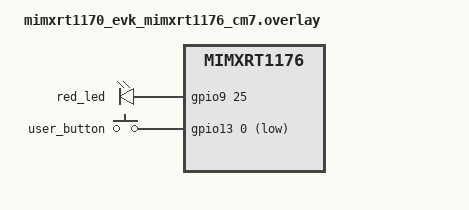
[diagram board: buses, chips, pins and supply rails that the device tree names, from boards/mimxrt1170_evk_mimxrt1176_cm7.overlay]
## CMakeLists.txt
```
# Copyright 2024-2026 NXP
# SPDX-License-Identifier: Apache-2.0

cmake_minimum_required(VERSION 3.20.0)

find_package(Zephyr REQUIRED HINTS $ENV{ZEPHYR_BASE})
project(android_link)

target_sources(app PRIVATE
  src/main.c
  src/touch.c
  src/display.c
  src/control_msg.c
)
target_sources_ifdef(CONFIG_ANDROID_LINK_MIC app PRIVATE src/mic_mode.c)

target_include_directories(app PRIVATE src)

if(CONFIG_NET_STACK_CODE_RELOCATE)
  # Relocate the networking stack and the L2 layer into the RAM named by
  # CONFIG_NET_STACK_CODE_RAM_NAME (ITCM on the RT1170), as the original demo does.
  zephyr_code_relocate(LIBRARY subsys__net__ip
    LOCATION "${CONFIG_NET_STACK_CODE_RAM_NAME}_TEXT" NOKEEP)
  zephyr_code_relocate(LIBRARY subsys__net
    LOCATION "${CONFIG_NET_STACK_CODE_RAM_NAME}_TEXT" NOKEEP)
  if(CONFIG_NET_L2_ETHERNET)
    zephyr_code_relocate(LIBRARY drivers__ethernet
      LOCATION "${CONFIG_NET_STACK_CODE_RAM_NAME}_TEXT" NOKEEP)
    zephyr_code_relocate(LIBRARY subsys__net__l2__ethernet
      LOCATION "${CONFIG_NET_STACK_CODE_RAM_NAME}_TEXT" NOKEEP)
  endif()
endif()
```

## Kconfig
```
# Copyright 2024-2026 NXP
# SPDX-License-Identifier: Apache-2.0

DT_CHOSEN_Z_DISPLAY := zephyr,display
DT_DISPLAY_PATH := $(dt_chosen_path,$(DT_CHOSEN_Z_DISPLAY))
DT_DISPLAY_WIDTH := $(dt_node_int_prop_int,$(DT_DISPLAY_PATH),width)
DT_DISPLAY_HEIGHT := $(dt_node_int_prop_int,$(DT_DISPLAY_PATH),height)
# A frame of the panel's size in RGB565
DT_DISPLAY_FRAME_SIZE := $(mul,$(mul,$(DT_DISPLAY_WIDTH),$(DT_DISPLAY_HEIGHT)),2)

# The decoder's pool holds frames of the panel's size
config MPIPE_IMG_JPEG_DECODER_MAX_OUT_FRAME_SIZE
	default $(DT_DISPLAY_FRAME_SIZE) if $(dt_chosen_enabled,$(DT_CHOSEN_Z_DISPLAY))

source "Kconfig.zephyr"

config ANDROID_LINK_FRAME_WIDTH
	int "Width of the frames the phone sends"
	default $(DT_DISPLAY_WIDTH)
	help
	  Width in pixels of the JPEG frames the phone streams, which the caps
	  filter pins behind the parser. It defaults to the width of the chosen
	  display and the phone's server must be launched with the same value
	  (WIDTH in its launch script).

config ANDROID_LINK_FRAME_HEIGHT
	int "Height of the frames the phone sends"
	default $(DT_DISPLAY_HEIGHT)
	help
	  Height in pixels of the JPEG frames the phone streams. It defaults to
	  the height of the chosen display and the phone's server must be
	  launched with the same value (HEIGHT in its launch script).

config NET_STACK_CODE_RELOCATE
	bool "Relocate networking code into RAM"
	select CODE_DATA_RELOCATION
	help
	  Relocate networking code into RAM. Can improve performance on
	  platforms with fast code RAM.

if NET_STACK_CODE_RELOCATE

config NET_STACK_CODE_RAM_NAME
	string "Networking code RAM location"
	default "RAM"
	help
	  Region to relocate networking code to

endif # NET_STACK_CODE_RELOCATE

config ANDROID_LINK_AUDIO
	bool "Play the phone's audio"
	default y
	depends on MPIPE_AUD
	help
	  Accept the phone's audio connection and play the raw PCM it carries
	  through a second pipeline ending in the I2S codec sink. The phone
	  must be launched with audio enabled and the raw codec.

config ANDROID_LINK_MIC
	bool "Send the board's microphone to the phone"
	default y
	depends on MPIPE_AUD && AUDIO_DMIC
	help
	  Accept a fourth connection from the phone, after the control one,
	  and send it the board's microphone as raw PCM, 16 kHz, 32-bit, two
	  channels, through a third pipeline from the DMIC source to a socket
	  sink. What the phone does with the stream, play it on its speaker,
	  feed it to the applications recording from its microphone, or drop
	  it, is set by a control message. The phone must be launched with the
	  microphone channel enabled.

config ANDROID_LINK_MIC_GAIN
	int "Gain applied to the board's microphone, in percent"
	depends on ANDROID_LINK_MIC
	range 0 1000
	default 200
	help
	  Gain of the aud_gain element in the microphone pipeline, 100 for
	  unity. A digital microphone's speech peaks well below full scale;
	  200 (+6 dB) brings it to the level of a phone's microphone. 0 mutes.

config ANDROID_LINK_PORT
	int "TCP port the board listens on"
	range 1 65535
	default 5000
	help
	  Port of the listening socket the phone's server connects to for the
	  video, audio, control and microphone streams (REMOTE_PORT in its
	  launch script).

if WIFI

config ANDROID_LINK_WIFI_SSID
	string "Name of the board's Wi-Fi network"
	default "zephyr-link"
	help
	  SSID of the soft-AP the board starts. The phone's server joins it
	  by itself when launched with the same name (WIFI_SSID).

config ANDROID_LINK_WIFI_PSK
	string "Passphrase of the board's Wi-Fi network"
	default "zephyrdemo"
	help
	  WPA2 passphrase of the soft-AP, at least 8 characters; empty for an
	  open network. The phone's server needs the same value (WIFI_PSK).

endif # WIFI

choice
	prompt "Control Event protocol"
	default CONTROL_EVENT_TCP

config CONTROL_EVENT_UDP
	bool "Control UDP protocol"
	help
	  Control events are reported using the UDP protocol.

config CONTROL_EVENT_TCP
	bool "Control TCP protocol"
	help
	  Touch events are reported using the TCP protocol.

endchoice
```

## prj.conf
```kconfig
#
# Copyright 2024-2026 NXP
#
# SPDX-License-Identifier: Apache-2.0
#

# Kernel options
CONFIG_MAIN_STACK_SIZE=8192
CONFIG_INIT_STACKS=y

# Shell
CONFIG_SHELL=y
CONFIG_NET_SHELL=y
CONFIG_DEVICE_SHELL=y

# Logging
CONFIG_PRINTK=y
CONFIG_LOG=y
CONFIG_NET_LOG=y

# Display
CONFIG_DISPLAY=y

# mpipe media pipeline framework
CONFIG_MPIPE=y
# Audio capabilities carry five fields; an intersection may hold one more
CONFIG_MPIPE_STRUCTURE_MAX_FIELDS=6
CONFIG_MPIPE_BASE=y
CONFIG_MPIPE_BASE_CAPS_FILTER=y
CONFIG_MPIPE_BASE_QUEUE=y
# Video: the source and two queues; audio and microphone: a source and a queue
# each; plus slack
CONFIG_MPIPE_THREADS_NUM=10
CONFIG_MPIPE_THREAD_STACK_SIZE=4096
CONFIG_MPIPE_NET=y
CONFIG_MPIPE_IMG=y
CONFIG_MPIPE_IMG_JPEG_DECODER=y
CONFIG_MPIPE_DISP=y
# The overlay draws the demo's messages on the frames; its text comes from the
# character framebuffer's built-in bitmap fonts
CONFIG_MPIPE_VID=y
CONFIG_MPIPE_VID_OVERLAY=y
CONFIG_CHARACTER_FRAMEBUFFER=y
CONFIG_CHARACTER_FRAMEBUFFER_USE_DEFAULT_FONTS=y
CONFIG_MPIPE_AUD=y
CONFIG_MPIPE_PLAYER=y
# One player per pipeline: video, audio and microphone
CONFIG_MPIPE_PLAYER_NUM=3
CONFIG_ZBUS_PRIORITY_BOOST=n

# Audio output: the I2S codec sink, fed 10 ms blocks of 48 kHz 16-bit stereo
# (1920 bytes) from a slab of up to 32 of them: 15 queued, up to 16 in the I2S
# driver's queue, the one being filled.
CONFIG_I2S=y
CONFIG_AUDIO_CODEC=y
CONFIG_MPIPE_AUD_BUFFER_POOL_SZ_MAX=4096
CONFIG_MPIPE_AUD_BUFFER_POOL_NUM_MAX=32

# Microphone input: the DMIC source, 10 ms blocks of 16 kHz 32-bit mono (640
# bytes) from a slab of its own: the driver's queue, 10 queued, slack. Two
# slabs, one per audio pipeline, each with a slice of the store.
CONFIG_AUDIO_DMIC=y
CONFIG_MPIPE_AUD_BUFFER_POOL_COUNT=2

# Longest JPEG frame accepted, and the size of the parser's copy buffers. A
# text-heavy 720x1280 screen compresses to well over 256 KB.
CONFIG_MPIPE_IMG_JPEG_PARSER_MAX_FRAME_SIZE=524288
CONFIG_MPIPE_IMG_JPEG_DECODER_MAX_OUT_FRAME_SIZE=1843200

# A frame inside one receive chunk reaches the decoder as a view of the chunk;
# only a frame split across two chunks is copied into one of these buffers.
CONFIG_MPIPE_IMG_JPEG_PARSER_POOL_NUM=4

# Buffer headers in flight across the three pipelines: the video views
# (pending input pieces, frames in the queues and in the decoder, decoded
# frames), the audio blocks in the audio queue and the I2S driver, the
# microphone blocks in the DMIC driver and the microphone queue, plus slack.
CONFIG_MPIPE_NET_BUF_POOL_COUNT=64

# Decoded frames in flight: one being decoded, one waiting in queue_dec, one
# being displayed, plus slack for a chain of frames decoded from one read.
CONFIG_MPIPE_IMG_JPEG_DECODER_POOL_NUM=6

# The queues between the threads are bounded and leak their oldest buffer
# (see main.c); this is the largest size a queue may be set to, the audio one.
CONFIG_MPIPE_BASE_QUEUE_MAX_SIZE=16

# The stream is received into 256 KB chunks, two to three frames each, and
# every frame inside a chunk reaches the decoder as a view of it. Four chunks:
# one being filled, one or two pinned by frames waiting or being decoded.
CONFIG_MPIPE_NET_SRC_BUF_SIZE=262144
CONFIG_MPIPE_NET_SRC_NUM_BUFS=4


# Generic networking options
CONFIG_NETWORKING=y
CONFIG_NET_STATISTICS=y
CONFIG_NET_TC_TX_COUNT=1
CONFIG_NET_SOCKETS=y
CONFIG_NET_SOCKETS_SERVICE_THREAD_PRIO=3

CONFIG_NET_IPV6=n
CONFIG_NET_IPV4=y
CONFIG_NET_IF_UNICAST_IPV4_ADDR_COUNT=1
CONFIG_NET_IF_MAX_IPV4_COUNT=2

CONFIG_NET_TCP=y
# Probe a silent phone: a Wi-Fi drop closes nothing by itself
CONFIG_NET_TCP_KEEPALIVE=y

# DHCPV4 Server & interface
CONFIG_NET_DHCPV4=y
CONFIG_NET_DHCPV4_SERVER=y

CONFIG_NET_CONTEXT_NET_PKT_POOL=y
CONFIG_NET_MAX_CONTEXTS=64

# Packet pools for the Ethernet and native_sim builds; overlay-wifi.conf sets
# larger ones. The defaults, 36 buffers of 128 bytes each way, hold under
# 5 KB: too little for a megabyte per second of video coming in and the
# microphone's 64 KB/s going out beside the acknowledgements.
CONFIG_NET_PKT_RX_COUNT=32
CONFIG_NET_PKT_TX_COUNT=32
CONFIG_NET_BUF_RX_COUNT=64
CONFIG_NET_BUF_TX_COUNT=64
CONFIG_NET_BUF_DATA_SIZE=1024

CONFIG_NET_MAX_CONN=64
CONFIG_NET_L2_ETHERNET=y

CONFIG_NET_CONFIG_SETTINGS=y
CONFIG_NET_CONFIG_MY_IPV4_ADDR="192.0.2.1"
CONFIG_NET_CONFIG_MY_IPV4_NETMASK="255.255.255.0"

CONFIG_SHELL_CMDS_RESIZE=n

CONFIG_CACHE_MANAGEMENT=y
CONFIG_SPEED_OPTIMIZATIONS=y

CONFIG_EVENTS=y

# Optimization for network
CONFIG_SYSTEM_WORKQUEUE_STACK_SIZE=4096
CONFIG_NET_TCP_WORKQ_STACK_SIZE=4096
CONFIG_NET_SOCKETS_SERVICE_STACK_SIZE=4096
CONFIG_NET_RX_STACK_SIZE=4096
CONFIG_NET_TX_STACK_SIZE=4096
CONFIG_NET_MGMT_EVENT_STACK_SIZE=4096

# Config Input: the touch controller and the user button
CONFIG_INPUT=y
CONFIG_GPIO=y
CONFIG_INPUT_GT911_MAX_TOUCH_POINTS=5
CONFIG_INPUT_QUEUE_MAX_MSGS=128
# The input thread runs the touch and button callbacks, a few comparisons and
# a queue put each. Above the audio (4) and video (5, decoder 6) threads: at
# Zephyr's default, the lowest priority, the decoder starved it, its queue
# filled with a finger's 4 events per 10 ms poll and releases were dropped.
CONFIG_INPUT_THREAD_PRIORITY_OVERRIDE=y
CONFIG_INPUT_THREAD_PRIORITY=3
CONFIG_NET_SOCKET_MAX_SEND_WAIT=10
```

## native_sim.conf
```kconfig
# Copyright 2026 NXP
# SPDX-License-Identifier: Apache-2.0
#
# Host-run convenience overlay for native_sim, applied by run_native_sim.sh.
# It is not used by a board build, so it changes nothing on the RT1170 target.

# Bind the native pty UART, and with it the Zephyr shell, to the process stdin
# and stdout rather than a separate pseudo-tty. The interactive player prompt
# (p/s/r/q) then appears in the terminal that launched the script.
CONFIG_UART_NATIVE_PTY_0_ON_STDINOUT=y

# With the shell sharing that one terminal, route the log output through the
# shell backend so log lines are serialized with the prompt instead of
# interleaving with and corrupting the line being typed.
CONFIG_SHELL_LOG_BACKEND=y
```

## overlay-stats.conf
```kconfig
# Copyright 2026 NXP
# SPDX-License-Identifier: Apache-2.0
#
# Investigation aid: per-thread CPU accounting and stack usage from the shell
# ("kernel threads", "kernel stacks", "net stats"), with a log buffer large
# enough for the per-second stage statistics. Logging stays deferred: in
# immediate mode every thread writes to the console itself, and a burst of
# errors then stalls the threads behind a 115200 baud UART.

CONFIG_THREAD_RUNTIME_STATS=y
CONFIG_THREAD_NAME=y
CONFIG_THREAD_MONITOR=y
CONFIG_THREAD_STACK_INFO=y
CONFIG_INIT_STACKS=y
CONFIG_KERNEL_SHELL=y
CONFIG_NET_SHELL=y
CONFIG_LOG_BUFFER_SIZE=8192

# The per-second stage statistics (socket source, parser, decoder, display sink)
CONFIG_MPIPE_STAGE_STATS=y
```

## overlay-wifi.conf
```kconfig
#
# Copyright 2024-2026 NXP
#
# SPDX-License-Identifier: Apache-2.0
#

# Zephyr Wi-Fi configuration for MURATA IW61x

# Config WIFI
CONFIG_WIFI=y
CONFIG_NXP_WIFI_SOFTAP_SUPPORT=y
CONFIG_ETH_NXP_ENET=n
CONFIG_MDIO_NXP_ENET=n
CONFIG_ETH_PHY_DRIVER=n
CONFIG_WIFI_NXP=y
CONFIG_NXP_IW61X=y
CONFIG_NXP_WIFI_SHELL=y
CONFIG_NXP_IW612_MURATA_2EL_M2=y
CONFIG_NET_DHCPV4_SERVER_ADDR_COUNT=32
CONFIG_NET_DHCPV4_SERVER_ICMP_PROBE_TIMEOUT=100
CONFIG_NET_L2_WIFI_SHELL=y
CONFIG_NET_L2_WIFI_MGMT=y

CONFIG_THREAD_CUSTOM_DATA=y
CONFIG_EVENTS=y
CONFIG_SYS_HEAP_AUTO=y
CONFIG_SCHED_MULTIQ=y

#firmware
CONFIG_NXP_MONOLITHIC_WIFI=y

# wifi driver
CONFIG_WIFI_SHELL_MAX_AP_STA=8
CONFIG_WIFI_MGMT_AP_MAX_NUM_STA=8
CONFIG_NXP_WIFI_TX_TASK_STACK_SIZE=4096
CONFIG_NXP_WIFI_DRIVER_TASK_STACK_SIZE=4096
CONFIG_NXP_WIFI_POWERSAVE_TASK_STACK_SIZE=4096
# net threads priority
CONFIG_IDLE_STACK_SIZE=1024

CONFIG_NET_MGMT_EVENT_QUEUE_SIZE=40

CONFIG_NET_CONFIG_AUTO_INIT=n

# CONFIG_WIFI_LOG_LEVEL_DBG=y
# CONFIG_NXP_WIFI_EXTRA_DEBUG=y
# CONFIG_NXP_WIFI_NET_DEBUG=y
# CONFIG_NXP_WIFI_WLCMGR_DEBUG=y
# CONFIG_NXP_WIFI_UAP_DEBUG=y
# CONFIG_NXP_WIFI_PKT_DEBUG=y

CONFIG_NXP_WIFI_SOFTAP_IP_ADDRESS="192.0.2.1"
CONFIG_NXP_WIFI_SOFTAP_IP_GATEWAY="192.0.2.1"
CONFIG_NXP_WIFI_SOFTAP_IP_MASK="255.255.255.0"
# DHCPv4 pool base must not overlap the soft-AP/server address (192.0.2.1).
CONFIG_NXP_WIFI_SOFTAP_IP_BASE="192.0.2.10"

# Lets the NXP Wi-Fi driver move its receive and transmit paths into the TCMs.
CONFIG_CODE_DATA_RELOCATION_SRAM=y

CONFIG_NET_PKT_RX_COUNT=96
CONFIG_NET_PKT_TX_COUNT=96
CONFIG_NET_BUF_RX_COUNT=128
CONFIG_NET_BUF_TX_COUNT=128
# Must be a multiple of MLAN_SDIO_BLOCK_SIZE (256) for the NXP WiFi
# SDIO zero-copy TX/RX path (see wifi-sdio.c compile-time assertion).
CONFIG_NET_BUF_DATA_SIZE=2560
CONFIG_NET_TC_TX_COUNT=1
CONFIG_NET_TC_RX_COUNT=1
CONFIG_NET_MGMT_EVENT_QUEUE_SIZE=20
CONFIG_NET_IF_MAX_IPV4_COUNT=3
CONFIG_NET_IPV4_FRAGMENT=y
CONFIG_NET_IPV4_FRAGMENT_MAX_COUNT=3
CONFIG_NET_IPV4_FRAGMENT_MAX_PKT=7
CONFIG_NET_IPV4_FRAGMENT_TIMEOUT=3
CONFIG_NET_L2_ETHERNET=y


CONFIG_SDIO_STACK=y
CONFIG_SD_CMD_RETRIES=3
CONFIG_SD_RETRY_COUNT=0

# CONFIG_NXP_WIFI_IO_DEBUG=y
# CONFIG_SD_LOG_LEVEL_DBG=y
# CONFIG_NXP_WIFI_PKT_DEBUG=y

CONFIG_NET_DEFAULT_IF_WIFI=y
CONFIG_SCHED_MULTIQ=y
CONFIG_NXP_WIFI_TX_RX_ZERO_COPY=y
CONFIG_NXP_WIFI_WMM_UAPSD=n
CONFIG_NXP_WIFI_ROAMING=n
CONFIG_NXP_WIFI_AUTO_POWER_SAVE=n
```

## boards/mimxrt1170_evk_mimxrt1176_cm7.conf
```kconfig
# Copyright 2026 NXP
# SPDX-License-Identifier: Apache-2.0

# Set the SDRAM up through the device configuration data block rather than the
# board's default external memory configuration data. Everything this sample
# streams through lives in SDRAM.
CONFIG_DEVICE_CONFIGURATION_DATA=y

# Run the networking stack from ITCM rather than from the XIP flash.
CONFIG_NET_STACK_CODE_RELOCATE=y
CONFIG_NET_STACK_CODE_RAM_NAME="ITCM"

# Audio: the WM8962 codec on the EVKB, configured over I3C, fed by SAI1
CONFIG_I3C=y
CONFIG_AUDIO_CODEC_WM8962=y
CONFIG_DMA_TCD_QUEUE_SIZE=4

# The phone sends its audio in real time, so the only margin against Wi-Fi
# jitter is what the I2S sink queues before it starts: 100 ms, out of a
# driver queue of 16 blocks. An underrun restarts the stream with a gap.
CONFIG_I2S_TX_BLOCK_COUNT=16
CONFIG_MPIPE_AUD_I2S_SINK_PRIME_BLOCKS=10

# Read the touch controller when its interrupt line says it has a report, rather
# than polling it every 10 ms: a sample is read when it happens.
CONFIG_INPUT_GT911_INTERRUPT=y
```

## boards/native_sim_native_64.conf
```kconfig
#
# Copyright 2024-2026 NXP
#
# SPDX-License-Identifier: Apache-2.0
#

# native_sim runs on the host: use the SDL display and SDL pointer input
# instead of the MIPI panel / GT911 touch controller of the hardware target.
CONFIG_SDL_DISPLAY=y
CONFIG_INPUT=y
CONFIG_INPUT_SDL_TOUCH=y

# Networking is provided by the native TAP Ethernet driver on the host.
CONFIG_ETH_NATIVE_TAP=y
CONFIG_NET_L2_ETHERNET=y

# The following options are only meaningful on the Cortex-M hardware target
# and must be disabled for the host build.
CONFIG_CACHE_MANAGEMENT=n
CONFIG_NET_STACK_CODE_RELOCATE=n

# Verbose mpipe logging to trace pipeline negotiation and per-frame display
# writes while bringing up the sample on native_sim.
CONFIG_LOG=y
CONFIG_MPIPE_LOG_LEVEL_DBG=y


# Audio on the host: the emulated I2S writes what it is given to a file, the
# dummy codec accepts any configuration.
CONFIG_I2S=y
CONFIG_I2S_NATIVE_SIM=y
CONFIG_AUDIO_CODEC=y
CONFIG_AUDIO_CODEC_DUMMY=y
CONFIG_I2S_NATIVE_SIM_TX_FILE_PATH="build/android_link_audio_tx.pcm"

# Microphone on the host: the emulated DMIC
CONFIG_AUDIO_DMIC=y
CONFIG_AUDIO_DMIC_NATIVE_SIM=y
```

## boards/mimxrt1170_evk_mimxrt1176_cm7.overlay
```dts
/*
 * Copyright 2026 NXP
 *
 * SPDX-License-Identifier: Apache-2.0
 */

/* The codec takes its master clock from the SAI */
&sai1 {
	mclk-output;
};

/*
 * The board file declares the red user LED D34 active low; on the EVKB rev B
 * it lights on a high level. The microphone mode shows on it.
 */
&red_led {
	gpios = <&gpio9 25 GPIO_ACTIVE_HIGH>;
};

/* Likewise the user button SW7: declared active high, pressed is low on the EVKB rev B */
&user_button {
	gpios = <&gpio13 0 GPIO_ACTIVE_LOW>;
};

/*
 * The on-board digital microphone: both slots of PDM data line 0. The
 * controller's output range adjustment, in dB, lifts the soft signal of the
 * microphone (speech peaked near -18 dB full scale on the phone) by 6 dB.
 */
dmic_dev: &micfil {
	channel0: micfil-channel@0 {
		status = "okay";
		decimation-filter-gain = <6>;
	};

	channel1: micfil-channel@1 {
		status = "okay";
		decimation-filter-gain = <6>;
	};
};
```

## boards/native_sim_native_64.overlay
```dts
/*
 * Copyright 2024-2026 NXP
 *
 * SPDX-License-Identifier: Apache-2.0
 */

/*
 * native_sim uses the SDL display and the SDL pointer input already declared
 * by the board devicetree (chosen zephyr,display = &sdl_dc and
 * zephyr,touch = &input_sdl_touch). The window takes the size of a phone's
 * screen in portrait; the frame size the sample expects follows it
 * (CONFIG_ANDROID_LINK_FRAME_WIDTH/HEIGHT) and the sender must stream that
 * size. The audio goes to the emulated I2S through the dummy codec, and the
 * microphone is the emulated DMIC.
 */

/ {
	aliases {
		i2s-codec-tx = &i2s_tx0;
	};
};

&sdl_dc {
	compatible = "zephyr,sdl-dc";
	width = <720>;
	height = <1280>;
};

dmic_dev: &dmic0 {
	status = "okay";
};

&i2s_tx0 {
	status = "okay";
};

&audio_codec {
	status = "okay";
};
```

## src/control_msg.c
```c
/*
 * Copyright (C) 2018 Genymobile
 * Copyright (C) 2018-2025 Romain Vimont
 *
 * Licensed under the Apache License, Version 2.0 (the "License");
 * you may not use this file except in compliance with the License.
 * You may obtain a copy of the License at
 *
 *    http://www.apache.org/licenses/LICENSE-2.0
 *
 * Unless required by applicable law or agreed to in writing, software
 * distributed under the License is distributed on an "AS IS" BASIS,
 * WITHOUT WARRANTIES OR CONDITIONS OF ANY KIND, either express or implied.
 * See the License for the specific language governing permissions and
 * limitations under the License.
 */
#include "control_msg.h"

#include <assert.h>
#include <inttypes.h>
#include <stdlib.h>
#include <string.h>

#include "util/binary.h"

static void write_position(uint8_t *buf, const struct sc_position *position)
{
	sc_write32be(&buf[0], position->point.x);
	sc_write32be(&buf[4], position->point.y);
	sc_write16be(&buf[8], position->screen_size.width);
	sc_write16be(&buf[10], position->screen_size.height);
}

size_t sc_control_msg_serialize(const struct sc_control_msg *msg, unsigned char *buf)
{
	buf[0] = msg->type;
	switch (msg->type) {
	case SC_CONTROL_MSG_TYPE_INJECT_TOUCH_EVENT:
		buf[1] = msg->inject_touch_event.action;
		sc_write64be(&buf[2], msg->inject_touch_event.pointer_id);
		write_position(&buf[10], &msg->inject_touch_event.position);
		uint16_t pressure = sc_float_to_u16fp(msg->inject_touch_event.pressure);
		sc_write16be(&buf[22], pressure);
		sc_write32be(&buf[24], msg->inject_touch_event.action_button);
		sc_write32be(&buf[28], msg->inject_touch_event.buttons);
		return 32;
	case SC_CONTROL_MSG_TYPE_KEEP_ALIVE:
		return 1;
	case SC_CONTROL_MSG_TYPE_SET_MIC_MODE:
		buf[1] = msg->set_mic_mode.mode;
		return 2;
	default:
		return 0;
	}
}
```

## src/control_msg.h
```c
/*
 * Copyright (C) 2018 Genymobile
 * Copyright (C) 2018-2025 Romain Vimont
 *
 * Licensed under the Apache License, Version 2.0 (the "License");
 * you may not use this file except in compliance with the License.
 * You may obtain a copy of the License at
 *
 *    http://www.apache.org/licenses/LICENSE-2.0
 *
 * Unless required by applicable law or agreed to in writing, software
 * distributed under the License is distributed on an "AS IS" BASIS,
 * WITHOUT WARRANTIES OR CONDITIONS OF ANY KIND, either express or implied.
 * See the License for the specific language governing permissions and
 * limitations under the License.
 */

#ifndef __SC_CONTROLMSG_H__
#define __SC_CONTROLMSG_H__

#include <stdbool.h>
#include <stddef.h>
#include <stdint.h>

#include "android/input.h"
#include "android/keycodes.h"
#include "coords.h"

/* The longest message this side sends, the touch event; the clipboard text, which sized
 * the original constant at 256k, never leaves the board.
 */
#define SC_CONTROL_MSG_MAX_SIZE 32

/*
 * The types above 100 are the demo's own, understood by its server build only;
 * the scrcpy types stop well below.
 */
enum sc_control_msg_type {
	SC_CONTROL_MSG_TYPE_INJECT_KEYCODE = 0,
	SC_CONTROL_MSG_TYPE_INJECT_TOUCH_EVENT = 2,
	SC_CONTROL_MSG_TYPE_KEEP_ALIVE = 100,
	SC_CONTROL_MSG_TYPE_SET_MIC_MODE = 101,
	SC_CONTROL_MSG_TYPE_SET_AUDIO_SOURCE = 102,
	/* The phone's client exits for good instead of reconnecting */
	SC_CONTROL_MSG_TYPE_QUIT = 103,
};

/* What the phone sends on its audio connection */
enum sc_audio_source {
	/* What it plays: media, games */
	SC_AUDIO_SOURCE_PLAYBACK = 0,
	/* Its microphone, with its own echo cancelling */
	SC_AUDIO_SOURCE_MIC = 1,
};

/* What the phone does with the microphone stream the board sends it */
enum sc_mic_mode {
	/* Discard it */
	SC_MIC_MODE_OFF = 0,
	/* Play it on the phone's speaker */
	SC_MIC_MODE_SPEAKER = 1,
	/* Feed it to the applications recording from the phone's microphone */
	SC_MIC_MODE_INJECT = 2,
};

struct sc_control_msg {
	enum sc_control_msg_type type;
	union {
		struct {
			enum android_keyevent_action action;
			enum android_keycode keycode;
			uint32_t repeat;
			enum android_metastate metastate;
		} inject_keycode;
		struct {
			enum android_motionevent_action action;
			enum android_motionevent_buttons action_button;
			enum android_motionevent_buttons buttons;
			uint64_t pointer_id;
			struct sc_position position;
			float pressure;
		} inject_touch_event;
		struct {
			enum sc_mic_mode mode;
		} set_mic_mode;
		struct {
			enum sc_audio_source source;
		} set_audio_source;
	};
};

// buf size must be at least CONTROL_MSG_MAX_SIZE
// return the number of bytes written
size_t sc_control_msg_serialize(const struct sc_control_msg *msg, unsigned char *buf);

#endif /*__SC_CONTROLMSG_H__*/
```

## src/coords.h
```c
/*
 * Copyright (C) 2018 Genymobile
 * Copyright (C) 2018-2025 Romain Vimont
 *
 * Licensed under the Apache License, Version 2.0 (the "License");
 * you may not use this file except in compliance with the License.
 * You may obtain a copy of the License at
 *
 *    http://www.apache.org/licenses/LICENSE-2.0
 *
 * Unless required by applicable law or agreed to in writing, software
 * distributed under the License is distributed on an "AS IS" BASIS,
 * WITHOUT WARRANTIES OR CONDITIONS OF ANY KIND, either express or implied.
 * See the License for the specific language governing permissions and
 * limitations under the License.
 */

#ifndef SC_COORDS
#define SC_COORDS

#include <stdint.h>

struct sc_size {
	uint16_t width;
	uint16_t height;
};

struct sc_point {
	int32_t x;
	int32_t y;
};

struct sc_position {
	// The video screen size may be different from the real device screen size,
	// so store to which size the absolute position apply, to scale it
	// accordingly.
	struct sc_size screen_size;
	struct sc_point point;
};

#endif
```

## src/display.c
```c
/*
 * Copyright 2024-2026 NXP
 *
 * SPDX-License-Identifier: Apache-2.0
 */

#include <zephyr/kernel.h>
#include <zephyr/drivers/display.h>

#include "screen.h"

#define LOG_LEVEL CONFIG_LOG_DEFAULT_LEVEL
#include <zephyr/logging/log.h>
LOG_MODULE_REGISTER(display);

int display_setup(const struct device *const display_dev)
{
	int ret;

	if (!device_is_ready(display_dev)) {
		LOG_ERR("Device %s not found\n", display_dev->name);
		return -ENODEV;
	}

	LOG_INF("Display device: %s\n", display_dev->name);

	ret = display_set_pixel_format(display_dev, SCR_FORMAT);
	if (ret < 0) {
		LOG_ERR("Unable to set pixel format");
		return ret;
	}

	return display_blanking_off(display_dev);
}
```

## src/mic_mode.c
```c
/*
 * Copyright 2026 NXP
 *
 * SPDX-License-Identifier: Apache-2.0
 */

/*
 * The demo mode: what the phone does with the board's microphone, and what it
 * sends on its audio connection. The streams always flow while the phone is
 * connected; the mode only says what each side does with them. It outlives a
 * connection, so a phone that reconnects is told the mode in force.
 *
 * The modes name where the board's microphone goes: nowhere (mute), the
 * phone's speaker (speaker), the phone's applications as if the board were
 * its headset (headset), and intercom, where the phone sends its own
 * microphone instead of its playback. A short press of the user button
 * cycles them in that order; a press held longer wakes the phone's voice
 * assistant instead, as a headset button does, which is how the assistant is
 * called from across the room since its wake word cannot hear the board; a
 * press held for seconds ends the demo: the phone's client exits instead of
 * reconnecting. The green LED is lit when the board's microphone plays on the
 * phone (speaker, intercom), the red one when the phone's microphone is
 * involved (headset, intercom). The shell commands
 * "mode" and "assist" do the same from a terminal, and are all there is on a
 * board without button or LEDs. Each action is shown on the panel for a
 * moment.
 */

#include <zephyr/kernel.h>
#include <zephyr/drivers/gpio.h>
#include <zephyr/input/input.h>
#include <zephyr/shell/shell.h>

#include "osd.h"
#include "screen.h"

#define LOG_LEVEL CONFIG_LOG_DEFAULT_LEVEL
#include <zephyr/logging/log.h>
LOG_MODULE_REGISTER(demo_mode);

/* A press held this long calls the assistant instead of changing the mode */
#define LONG_PRESS_MS 700
/* A press held this long ends the demo on the phone */
#define QUIT_PRESS_MS 3000
/* How long a message stays on the panel */
#define OSD_MS        2000

#define LED_GREEN_NODE DT_ALIAS(led0)
#define LED_RED_NODE   DT_ALIAS(led1)

#if DT_NODE_HAS_STATUS_OKAY(LED_GREEN_NODE)
static const struct gpio_dt_spec led_green = GPIO_DT_SPEC_GET(LED_GREEN_NODE, gpios);
#else
static const struct gpio_dt_spec led_green;
#endif

#if DT_NODE_HAS_STATUS_OKAY(LED_RED_NODE)
static const struct gpio_dt_spec led_red = GPIO_DT_SPEC_GET(LED_RED_NODE, gpios);
#else
static const struct gpio_dt_spec led_red;
#endif

/*
 * Start with the microphone muted: a phone lying next to the board would
 * otherwise feed its own speaker back through the board's microphone.
 */
static enum demo_mode demo_mode = DEMO_MODE_MUTE;

/* What each mode asks of the phone */
static const struct {
	const char *name;
	enum sc_mic_mode mic_mode;
	enum sc_audio_source audio_source;
	bool green;
	bool red;
} modes[] = {
	[DEMO_MODE_MUTE] = {"mute", SC_MIC_MODE_OFF, SC_AUDIO_SOURCE_PLAYBACK, false, false},
	[DEMO_MODE_SPEAKER] = {"speaker", SC_MIC_MODE_SPEAKER, SC_AUDIO_SOURCE_PLAYBACK, true,
			       false},
	[DEMO_MODE_HEADSET] = {"headset", SC_MIC_MODE_INJECT, SC_AUDIO_SOURCE_PLAYBACK, false,
			       true},
	[DEMO_MODE_INTERCOM] = {"intercom", SC_MIC_MODE_SPEAKER, SC_AUDIO_SOURCE_MIC, true, true},
};

const char *demo_mode_name(enum demo_mode mode)
{
	return (mode < ARRAY_SIZE(modes)) ? modes[mode].name : "?";
}

enum demo_mode demo_mode_get(void)
{
	return demo_mode;
}

static void led_init(const struct gpio_dt_spec *led)
{
	if (led->port != NULL && gpio_is_ready_dt(led)) {
		(void)gpio_pin_configure_dt(led, GPIO_OUTPUT_INACTIVE);
	}
}

static void led_show(const struct gpio_dt_spec *led, bool on)
{
	if (led->port != NULL) {
		(void)gpio_pin_set_dt(led, on ? 1 : 0);
	}
}

void demo_mode_announce(void)
{
	control_send_mic_mode(modes[demo_mode].mic_mode);
	control_send_audio_source(modes[demo_mode].audio_source);
}

void demo_mode_set(enum demo_mode mode)
{
	if (mode >= ARRAY_SIZE(modes)) {
		return;
	}

	demo_mode = mode;
	led_show(&led_green, modes[mode].green);
	led_show(&led_red, modes[mode].red);
	LOG_INF("Mode: %s", modes[mode].name);
	osd_show(modes[mode].name, OSD_MS);
	demo_mode_announce();
}

static void assist(void)
{
	LOG_INF("Calling the assistant");
	osd_show("Assistant", OSD_MS);
	control_send_key(AKEYCODE_VOICE_ASSIST);
}

static void quit_phone(void)
{
	LOG_INF("Ending the demo on the phone");
	osd_show("Bye", OSD_MS);
	control_send_quit();
}

void demo_mode_init(void)
{
	led_init(&led_green);
	led_init(&led_red);
	demo_mode_set(demo_mode);
}

#if DT_HAS_COMPAT_STATUS_OKAY(gpio_keys)
/*
 * How long the button has been held, in stages: a release in stage 0 is a
 * short press, in stage 1 it calls the assistant, and stage 2 is reached while
 * still held and ends the demo at once.
 */
static uint8_t press_stage;

/*
 * The release event can be lost: it goes through the input queue with the
 * touch panel's events, which fill it when the panel is busy. So each timer
 * reads the button itself and a button found up is a release at that stage.
 */
#if DT_NODE_HAS_STATUS_OKAY(DT_ALIAS(sw0))
static const struct gpio_dt_spec button = GPIO_DT_SPEC_GET(DT_ALIAS(sw0), gpios);
#else
static const struct gpio_dt_spec button;
#endif

static bool button_held(void)
{
	return button.port == NULL || gpio_pin_get_dt(&button) != 0;
}

/* What a release does at the stage the press reached */
static void release_work_fn(struct k_work *work)
{
	ARG_UNUSED(work);

	switch (press_stage) {
	case 0:
		demo_mode_set((demo_mode + 1) % ARRAY_SIZE(modes));
		break;
	case 1:
		assist();
		break;
	default:
		break;
	}
}

static K_WORK_DEFINE(release_work, release_work_fn);

static void press_timer_fn(struct k_timer *timer)
{
	if (!button_held()) {
		k_work_submit(&release_work);
		return;
	}

	if (press_stage == 0U) {
		press_stage = 1;
		osd_show("Assistant", OSD_MS);
		k_timer_start(timer, K_MSEC(QUIT_PRESS_MS - LONG_PRESS_MS), K_NO_WAIT);
	} else {
		press_stage = 2;
		quit_phone();
	}
}

static K_TIMER_DEFINE(press_timer, press_timer_fn, NULL);

static void button_cb(struct input_event *evt, void *user_data)
{
	ARG_UNUSED(user_data);

	if (evt->type != INPUT_EV_KEY || evt->code != INPUT_KEY_0) {
		return;
	}

	if (evt->value != 0) {
		press_stage = 0;
		k_timer_start(&press_timer, K_MSEC(LONG_PRESS_MS), K_NO_WAIT);
		return;
	}

	k_timer_stop(&press_timer);
	k_work_submit(&release_work);
}

INPUT_CALLBACK_DEFINE(DEVICE_DT_GET_ANY(gpio_keys), button_cb, NULL);
#endif

#if defined(CONFIG_SHELL)
static int cmd_mode(const struct shell *sh, size_t argc, char **argv)
{
	if (argc < 2) {
		shell_print(sh, "Mode: %s", modes[demo_mode].name);
		return 0;
	}

	for (size_t i = 0; i < ARRAY_SIZE(modes); i++) {
		if (strcmp(argv[1], modes[i].name) == 0) {
			demo_mode_set(i);
			return 0;
		}
	}

	shell_error(sh, "Unknown mode %s", argv[1]);
	return -EINVAL;
}

SHELL_CMD_ARG_REGISTER(mode, NULL, "Demo mode: mode [mute|speaker|headset|intercom]", cmd_mode, 1,
		       1);

static int cmd_assist(const struct shell *sh, size_t argc, char **argv)
{
	ARG_UNUSED(sh);
	ARG_UNUSED(argc);
	ARG_UNUSED(argv);

	assist();

	return 0;
}

SHELL_CMD_REGISTER(assist, NULL, "Call the phone's voice assistant", cmd_assist);

static int cmd_phone_quit(const struct shell *sh, size_t argc, char **argv)
{
	ARG_UNUSED(sh);
	ARG_UNUSED(argc);
	ARG_UNUSED(argv);

	quit_phone();

	return 0;
}

SHELL_STATIC_SUBCMD_SET_CREATE(phone_cmds,
			       SHELL_CMD(quit, NULL, "End the demo on the phone", cmd_phone_quit),
			       SHELL_SUBCMD_SET_END);
SHELL_CMD_REGISTER(phone, &phone_cmds, "The phone's client", NULL);
#endif
```

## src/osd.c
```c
/*
 * Copyright 2026 NXP
 *
 * SPDX-License-Identifier: Apache-2.0
 */

#include <string.h>

#include <zephyr/kernel.h>
#include <zephyr/drivers/display.h>
#include <zephyr/drivers/video.h>
#include <zephyr/spinlock.h>

#include <zephyr/mpipe/vid/mpipe_vid_draw.h>

#include "osd.h"
#include "screen.h"

#define LOG_LEVEL CONFIG_LOG_DEFAULT_LEVEL
#include <zephyr/logging/log.h>
LOG_MODULE_REGISTER(osd);

#define OSD_BAND_HEIGHT 80
#define OSD_TEXT_SCALE  2
#define OSD_TEXT_MAX    32
#define OSD_BACKGROUND  0x000000
#define OSD_FOREGROUND  0xFFFFFF

static struct {
	struct k_spinlock lock;
	char text[OSD_TEXT_MAX];
	int64_t deadline;
	const struct device *display_dev;
	uint32_t painted;
	uint32_t frames;
	int64_t stats_at;
} osd;

/* The band the panel shows while nothing streams; the panel is RGB565 */
static uint8_t idle_band[SCR_WIDTH * OSD_BAND_HEIGHT * 2];

/* Paint the band with @p text centred into a frame or the idle buffer */
static void osd_paint(uint8_t *frame, uint16_t width, uint16_t height, uint32_t pixfmt,
		      const char *text)
{
	const struct mpipe_vid_rect band = {0, 0, width - 1, OSD_BAND_HEIGHT - 1};
	uint8_t scale = OSD_TEXT_SCALE;
	uint32_t tw = 0;
	uint32_t th = 0;
	int32_t x;
	int32_t y;

	(void)mpipe_vid_draw_fill(frame, width, height, pixfmt, &band, OSD_BACKGROUND);
	if (mpipe_vid_draw_text_size(scale, text, &tw, &th) != 0) {
		return;
	}

	/* A text too wide for the band is drawn smaller rather than cut */
	while (scale > 1U && tw > width) {
		scale--;
		(void)mpipe_vid_draw_text_size(scale, text, &tw, &th);
	}

	x = ((int32_t)width - (int32_t)tw) / 2;
	y = (OSD_BAND_HEIGHT - (int32_t)th) / 2;
	(void)mpipe_vid_draw_text(frame, width, height, pixfmt, MAX(x, 0), MAX(y, 0), scale,
				  OSD_FOREGROUND, text);
}

/* The overlay element's callback, once per frame on the display thread */
static void osd_draw(uint8_t *frame, uint16_t width, uint16_t height, uint32_t pixfmt,
		     void *user_data)
{
	char text[OSD_TEXT_MAX];
	k_spinlock_key_t key;
	bool active;

	ARG_UNUSED(user_data);

	key = k_spin_lock(&osd.lock);
	active = k_uptime_get() < osd.deadline;
	if (active) {
		memcpy(text, osd.text, sizeof(text));
	}
	k_spin_unlock(&osd.lock, key);

	if (active) {
		osd_paint(frame, width, height, pixfmt, text);
		osd.painted++;
	}
	osd.frames++;

	/* How many of the frames carried the band, once a second while one is shown */
	if (IS_ENABLED(CONFIG_MPIPE_STAGE_STATS) && k_uptime_get() - osd.stats_at >= 1000) {
		if (osd.painted > 0U) {
			LOG_INF("band on %u of %u frames", osd.painted, osd.frames);
		}
		osd.painted = 0;
		osd.frames = 0;
		osd.stats_at = k_uptime_get();
	}
}

void osd_show(const char *text, uint32_t ms)
{
	k_spinlock_key_t key = k_spin_lock(&osd.lock);

	strncpy(osd.text, text, sizeof(osd.text) - 1);
	osd.text[sizeof(osd.text) - 1] = '\0';
	osd.deadline = k_uptime_get() + ms;
	k_spin_unlock(&osd.lock, key);
}

void osd_idle(const char *text)
{
	const struct display_buffer_descriptor desc = {
		.buf_size = sizeof(idle_band),
		.width = SCR_WIDTH,
		.height = OSD_BAND_HEIGHT,
		.pitch = SCR_WIDTH,
	};
	int ret;

	if (osd.display_dev == NULL) {
		return;
	}

	osd_paint(idle_band, SCR_WIDTH, OSD_BAND_HEIGHT, VIDEO_PIX_FMT_RGB565, text);
	ret = display_write(osd.display_dev, 0, 0, &desc, idle_band);
	if (ret != 0) {
		LOG_WRN("Could not write the panel (%d)", ret);
	}
}

int osd_init(struct mpipe_vid_overlay *overlay, const struct device *display_dev)
{
	static const struct mpipe_vid_overlay_cb cb = {.fn = osd_draw};

	osd.display_dev = display_dev;

	return mpipe_object_set_properties((struct mpipe_object *)overlay,
					   MPIPE_PROP_VID_OVERLAY_DRAW_CB, &cb,
					   MPIPE_PROP_LIST_END);
}
```

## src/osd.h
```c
/*
 * Copyright 2026 NXP
 *
 * SPDX-License-Identifier: Apache-2.0
 */

#ifndef SCRMIRROR_OSD_H
#define SCRMIRROR_OSD_H

#include <stdint.h>

#include <zephyr/device.h>
#include <zephyr/mpipe/vid/mpipe_vid_overlay.h>

/*
 * Text on the panel: a band at the top of the frames the display sink shows,
 * drawn by the overlay element's callback while a message is active, and the
 * same band written to the panel directly while no phone streams.
 */

/* Set the overlay element's draw callback up and remember the panel */
int osd_init(struct mpipe_vid_overlay *overlay, const struct device *display_dev);
/* Show @p text on the frames for @p ms milliseconds; callable from any context */
void osd_show(const char *text, uint32_t ms);
/* Write @p text to the panel now, for when no pipeline draws on it */
void osd_idle(const char *text);

#endif
```

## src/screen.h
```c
/*
 * Copyright 2024-2026 NXP
 *
 * SPDX-License-Identifier: Apache-2.0
 */

#ifndef SCRMIRROR_SCREEN
#define SCRMIRROR_SCREEN

#include <zephyr/net/socket.h>

#include "control_msg.h"

#define SCR_WIDTH  DT_PROP(DT_CHOSEN(zephyr_display), width)
#define SCR_HEIGHT DT_PROP(DT_CHOSEN(zephyr_display), height)
#define SCR_BUF_SZ (SCR_WIDTH * SCR_HEIGHT * 2)
#define SCR_FORMAT PIXEL_FORMAT_RGB_565

#define EVENT_SOCKET_THREAD_STOP (1 << 1)
#define EVENT_TOUCH_ERROR        (1 << 2)
/* Pixels a finger must travel from the last point sent before a move is sent */
#define SENSITIVITY_RADIUS       2

/*
 * Maximum number of simultaneous touch points. The GT911 controller on the
 * rk055hdmipi4ma0 shield reports this through its own Kconfig; boards without
 * that driver (e.g. native_sim with the single-pointer SDL input) fall back
 * to a single touch point.
 */
#ifdef CONFIG_INPUT_GT911_MAX_TOUCH_POINTS
#define MAX_TOUCH_POINTS CONFIG_INPUT_GT911_MAX_TOUCH_POINTS
#else
#define MAX_TOUCH_POINTS 1
#endif

void control_init(void);
/*
 * Start sending touch events to the phone at @p client_addr: over @p control_fd,
 * the connection the phone opened for control, or over a UDP socket of its own.
 */
void connect_control_socket(int control_fd, struct sockaddr_in *client_addr);
int disconnect_control_socket(void);
bool control_socket_is_connected(void);
/* Tell the phone what to do with the microphone stream, and what to send; nothing when not connected */
void control_send_mic_mode(enum sc_mic_mode mode);
void control_send_audio_source(enum sc_audio_source source);
/* Press and release a key on the phone, as a headset button does */
void control_send_key(enum android_keycode keycode);
/* Tell the phone's client to exit for good */
void control_send_quit(void);

/*
 * What the demo does with the two audio streams, as one state the user button
 * cycles through. Each state is a microphone mode for the phone and a source
 * for the phone's audio connection.
 */
enum demo_mode {
	/* The phone's playback on the board, the board's microphone muted: the start mode */
	DEMO_MODE_MUTE,
	/* The phone's playback on the board, the board's microphone on the phone's speaker */
	DEMO_MODE_SPEAKER,
	/* The phone's playback on the board, the board's microphone as the phone's microphone */
	DEMO_MODE_HEADSET,
	/* The phone's microphone on the board, the board's microphone on the phone's speaker */
	DEMO_MODE_INTERCOM,
};

/*
 * Changing the mode sends the phone both messages when the control connection
 * is up; connecting announces the mode in force.
 */
enum demo_mode demo_mode_get(void);
void demo_mode_set(enum demo_mode mode);
void demo_mode_announce(void);
const char *demo_mode_name(enum demo_mode mode);
/* Set the LEDs up and show the initial mode */
void demo_mode_init(void);

int display_setup(const struct device *const display_dev);

#endif
```

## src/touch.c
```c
/*
 * Copyright 2024-2026 NXP
 *
 * SPDX-License-Identifier: Apache-2.0
 */

#include <zephyr/kernel.h>
#include <zephyr/kernel/thread.h>
#include <zephyr/input/input.h>
#include <zephyr/net/socket.h>
#include "screen.h"

#define LOG_LEVEL CONFIG_LOG_DEFAULT_LEVEL
#include <zephyr/logging/log.h>
LOG_MODULE_REGISTER(touch_report);

/*
 * Resolve the touch controller node. Boards that declare a
 * "zephyr,touch" chosen node (e.g. native_sim with the SDL pointer input)
 * use it directly; otherwise fall back to the GT911 controller node label
 * provided by the rk055hdmipi4ma0 display shield.
 */
#if DT_HAS_CHOSEN(zephyr_touch)
#define TOUCH_NODE DT_CHOSEN(zephyr_touch)
#else
#define TOUCH_NODE DT_NODELABEL(gt911_rk055hdmipi4ma0)
#endif

K_MSGQ_DEFINE(sc_control_queue, sizeof(struct sc_control_msg), CONFIG_INPUT_QUEUE_MAX_MSGS, 4);

static void check_alive(struct k_timer *dummy);
static K_TIMER_DEFINE(check_alive_timer, check_alive, NULL);
extern struct k_event application_event;

struct point_event {
	uint16_t x;
	uint16_t y;
	uint16_t state;
};

struct control_data {
	int control_socket;
	struct sockaddr_in *remote_addr;
	uint8_t actual_point_id;
	struct point_event prev_event[MAX_TOUCH_POINTS];
	struct point_event actual_event[MAX_TOUCH_POINTS];
	struct k_work send_work;
	bool is_connected;
};

static struct control_data data;

/*
 * The messages leave from a work queue of their own: on the system workqueue
 * a send that blocks on Wi-Fi held up the touch controller's poll, which runs
 * there too. Everything queued when the work runs goes in one send.
 */
#define CONTROL_SEND_BUF_SIZE     1024
#define CONTROL_SEND_STACK_SIZE   2048
#define CONTROL_SEND_THREAD_PRIO  3

static uint8_t msg_buf[CONTROL_SEND_BUF_SIZE];
static struct k_work_q send_q;
static K_KERNEL_STACK_DEFINE(send_q_stack, CONTROL_SEND_STACK_SIZE);

static bool has_touch_moved(const struct point_event *prev_point,
			    const struct point_event *actual_point)
{
	return actual_point->state == 1 && prev_point->state == 1 &&
	       (actual_point->x - prev_point->x) * (actual_point->x - prev_point->x) +
			       (actual_point->y - prev_point->y) *
				       (actual_point->y - prev_point->y) >=
		       SENSITIVITY_RADIUS * SENSITIVITY_RADIUS;
}

static void convert_to_android_event(struct sc_control_msg *android_point,
				     const struct point_event *actual_event,
				     const struct point_event *prev_event)
{
	android_point->type = SC_CONTROL_MSG_TYPE_INJECT_TOUCH_EVENT;
	android_point->inject_touch_event.position.point.x = actual_event->x;
	android_point->inject_touch_event.position.point.y = actual_event->y;
	android_point->inject_touch_event.position.screen_size.height = SCR_HEIGHT;
	android_point->inject_touch_event.position.screen_size.width = SCR_WIDTH;

	if (actual_event->state == 1 && prev_event->state == 0) {
		android_point->inject_touch_event.action = AMOTION_EVENT_ACTION_DOWN;
		android_point->inject_touch_event.pressure = 1.0;
	} else if (actual_event->state == 1 && prev_event->state == 1) {
		android_point->inject_touch_event.action = AMOTION_EVENT_ACTION_MOVE;
		android_point->inject_touch_event.pressure = 1.0;
	} else if (actual_event->state == 0 && prev_event->state == 1) {
		android_point->inject_touch_event.action = AMOTION_EVENT_ACTION_UP;
		android_point->inject_touch_event.pressure = 0.0;
	}

	android_point->inject_touch_event.buttons = 0;
	android_point->inject_touch_event.action_button = 0;
}

static void check_alive(struct k_timer *timer)
{
	struct control_data *p_data = k_timer_user_data_get(timer);
	struct sc_control_msg keep_alive = {0};

	keep_alive.type = SC_CONTROL_MSG_TYPE_KEEP_ALIVE;
	LOG_DBG("Check alive");
	if (p_data->is_connected && k_msgq_num_used_get(&sc_control_queue) == 0) {
		k_msgq_put(&sc_control_queue, &keep_alive, K_NO_WAIT);
		k_work_submit_to_queue(&send_q, &p_data->send_work);
	}
}

static void control_send(const struct sc_control_msg *msg)
{
	if (data.is_connected) {
		k_msgq_put(&sc_control_queue, msg, K_NO_WAIT);
		k_work_submit_to_queue(&send_q, &data.send_work);
	}
}

void control_send_mic_mode(enum sc_mic_mode mode)
{
	struct sc_control_msg msg = {
		.type = SC_CONTROL_MSG_TYPE_SET_MIC_MODE,
		.set_mic_mode.mode = mode,
	};

	control_send(&msg);
}

void control_send_key(enum android_keycode keycode)
{
	struct sc_control_msg msg = {
		.type = SC_CONTROL_MSG_TYPE_INJECT_KEYCODE,
		.inject_keycode.keycode = keycode,
		.inject_keycode.repeat = 0,
		.inject_keycode.metastate = AMETA_NONE,
	};

	msg.inject_keycode.action = AKEY_EVENT_ACTION_DOWN;
	control_send(&msg);
	msg.inject_keycode.action = AKEY_EVENT_ACTION_UP;
	control_send(&msg);
}

void control_send_quit(void)
{
	struct sc_control_msg msg = {.type = SC_CONTROL_MSG_TYPE_QUIT};

	control_send(&msg);
}

void control_send_audio_source(enum sc_audio_source source)
{
	struct sc_control_msg msg = {
		.type = SC_CONTROL_MSG_TYPE_SET_AUDIO_SOURCE,
		.set_audio_source.source = source,
	};

	control_send(&msg);
}

static void parse_touch_event_cb(struct input_event *evt, void *user_data)
{
	struct control_data *p_data = user_data;
	struct sc_control_msg actual_msg;

	switch (evt->code) {
	case INPUT_ABS_MT_SLOT:
		p_data->actual_point_id = evt->value < MAX_TOUCH_POINTS ? evt->value : 0;
		if (evt->value >= MAX_TOUCH_POINTS) {
			LOG_WRN("evt_value is greater than MAX_TOUCH_POINTS");
		}
		break;
	case INPUT_ABS_X:
		p_data->actual_event[p_data->actual_point_id].x = evt->value;
		break;
	case INPUT_ABS_Y:
		p_data->actual_event[p_data->actual_point_id].y = evt->value;
		break;
	case INPUT_BTN_TOUCH:
		p_data->actual_event[p_data->actual_point_id].state = evt->value;
		if (p_data->is_connected &&
		    (has_touch_moved(&p_data->prev_event[p_data->actual_point_id],
				     &p_data->actual_event[p_data->actual_point_id]) ||
		     p_data->prev_event[p_data->actual_point_id].state !=
			     p_data->actual_event[p_data->actual_point_id].state)) {
			actual_msg.inject_touch_event.pointer_id = p_data->actual_point_id;
			convert_to_android_event(&actual_msg,
						 &p_data->actual_event[p_data->actual_point_id],
						 &p_data->prev_event[p_data->actual_point_id]);

			k_msgq_put(&sc_control_queue, &actual_msg, K_NO_WAIT);
			k_work_submit_to_queue(&send_q, &p_data->send_work);
		}
		p_data->prev_event[p_data->actual_point_id] =
			p_data->actual_event[p_data->actual_point_id];
		break;
	}
}

static void send_work_handler(struct k_work *kwork)
{
	struct sc_control_msg android_evt_data;
	struct control_data *evt_send = CONTAINER_OF(kwork, struct control_data, send_work);

	while (k_msgq_num_used_get(&sc_control_queue) > 0) {
		size_t len = 0;
		ssize_t send_size;

		/* Serialize what is queued, as long as a longest message still fits */
		while (len + SC_CONTROL_MSG_MAX_SIZE <= sizeof(msg_buf) &&
		       k_msgq_get(&sc_control_queue, &android_evt_data, K_NO_WAIT) == 0) {
			len += sc_control_msg_serialize(&android_evt_data, &msg_buf[len]);
			LOG_DBG("Report touch point %u x: %d y: %d btn: %d",
				(unsigned int)android_evt_data.inject_touch_event.pointer_id,
				android_evt_data.inject_touch_event.position.point.x,
				android_evt_data.inject_touch_event.position.point.y,
				android_evt_data.inject_touch_event.action);
		}

		if (len == 0) {
			break;
		}

		if (IS_ENABLED(CONFIG_CONTROL_EVENT_TCP)) {
			send_size = zsock_send(evt_send->control_socket, msg_buf, len, 0);
		} else {
			send_size = zsock_sendto(evt_send->control_socket, msg_buf, len, 0,
						 (const struct sockaddr *)evt_send->remote_addr,
						 sizeof(struct sockaddr));
		}
		if (send_size <= 0) {
			LOG_ERR("Touch socket error");
			k_event_post(&application_event, EVENT_TOUCH_ERROR);
			return;
		}
	}
}

void connect_control_socket(int control_fd, struct sockaddr_in *client_addr)
{
	if (IS_ENABLED(CONFIG_CONTROL_EVENT_TCP)) {
		/* The connection the phone opened for control, accepted by the caller */
		data.control_socket = control_fd;

		/*
		 * Every message is a few bytes and must leave now: with Nagle a
		 * segment waits for the acknowledgment of the previous one, and the
		 * phone delays its acknowledgments, so moves left in bursts.
		 */
		if (zsock_setsockopt(control_fd, IPPROTO_TCP, TCP_NODELAY, &(int){1},
				     sizeof(int)) < 0) {
			LOG_WRN("Cannot disable Nagle on the control socket (%d)", errno);
		}
	} else {
		data.control_socket = zsock_socket(AF_INET, SOCK_DGRAM, IPPROTO_UDP);
	}

	if (data.control_socket < 0) {
		LOG_ERR("No control socket: %d", errno);
		return;
	}

	data.remote_addr = client_addr;

	data.is_connected = true;

	LOG_INF("%s control socket is connected",
		IS_ENABLED(CONFIG_CONTROL_EVENT_TCP) ? "TCP" : "UDP");

	k_timer_start(&check_alive_timer, K_MSEC(20000), K_MSEC(20000));
}

int disconnect_control_socket(void)
{
	int ret = 0;

	if (data.is_connected) {
		if (IS_ENABLED(CONFIG_CONTROL_EVENT_TCP)) {
			zsock_shutdown(data.control_socket, SHUT_RDWR);
		}

		ret = zsock_close(data.control_socket);
		if (ret < 0) {
			LOG_ERR("Cannot close the connection %d", errno);
			ret = -EIO;
		}

		data.is_connected = false;
		k_timer_stop(&check_alive_timer);

		LOG_INF("Control socket disconnected");
	}

	return ret;
}

bool control_socket_is_connected(void)
{
	return data.is_connected;
}

void control_init(void)
{
	k_work_queue_init(&send_q);
	k_work_queue_start(&send_q, send_q_stack, K_KERNEL_STACK_SIZEOF(send_q_stack),
			   CONTROL_SEND_THREAD_PRIO, NULL);
	k_thread_name_set(k_work_queue_thread_get(&send_q), "control_send");
	k_work_init(&data.send_work, send_work_handler);
	k_timer_user_data_set(&check_alive_timer, &data);
}

INPUT_CALLBACK_DEFINE(DEVICE_DT_GET(TOUCH_NODE), parse_touch_event_cb, &data);
```
